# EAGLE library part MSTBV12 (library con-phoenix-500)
PHOENIX

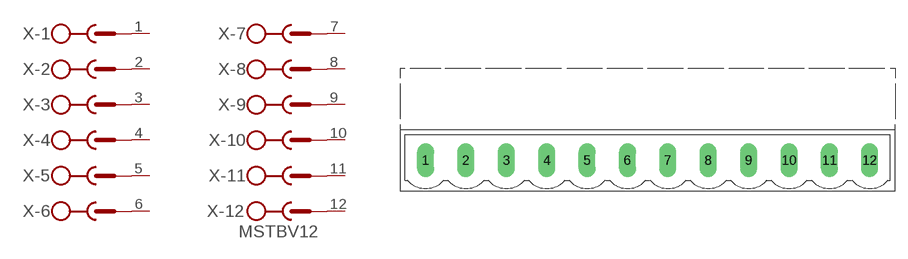
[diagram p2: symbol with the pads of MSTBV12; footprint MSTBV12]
Designator prefix X; gates -1=SK -2=SK -3=SK -4=SK -5=SK -6=SK -7=SK -8=SK -9=SK -10=SK -11=SK -12=SK+V

## MSTBV12 (OC_FARNELL: unknown; OC_NEWARK: unknown)  [MSTBV12]
1  -1:SK  pas
2  -2:SK  pas
3  -3:SK  pas
4  -4:SK  pas
5  -5:SK  pas
6  -6:SK  pas
7  -7:SK  pas
8  -8:SK  pas
9  -9:SK  pas
10  -10:SK  pas
11  -11:SK  pas
12  -12:SK  pas

## Footprint MSTBV12 (pad centres in mm)
PHOENIX
drill 1.397 long: 1 -27.5,0; 2 -22.496,0; 3 -17.492,0; 4 -12.489,0; 5 -7.51,0; 6 -2.506,0; 7 2.497,0; 8 7.501,0; 9 12.505,0; 10 17.509,0; 11 22.513,0; 12 27.491,0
